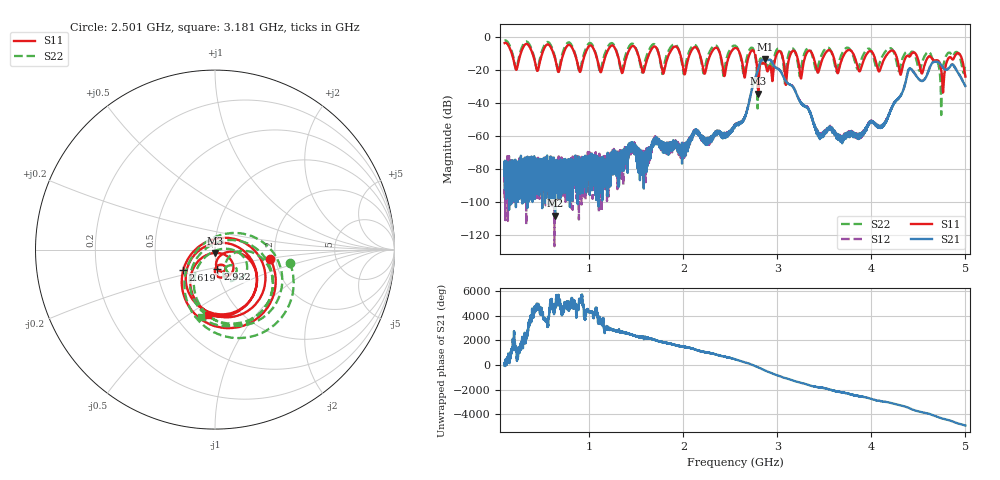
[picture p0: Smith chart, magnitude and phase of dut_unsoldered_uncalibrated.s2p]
!Keysight Technologies N9917A: A.13.25
!Date: Thursday, 15 October 2026 16:12:21
!Timezone: (UTC-08:00) Pacific Time (US & Canada)
!Model: N9917A
!Serial: MY56072049
!GPS Latitude:
!GPS Longitude:
!GPS TimeStamp: 0001-01-01 00:00:00Z
!GPS Seconds Since Last Read: 0
!CHECKSUM:0079315714
!Correction: S11(Rdy)S21(Rdy)S12(Rdy)S22(Rdy)
!S2P File: Measurements:S11,S21,S12,S22:
# Hz S DB R 50
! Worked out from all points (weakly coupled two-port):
!   10001 points, 100 MHz to 5 GHz, reference 50 ohm
!   highest |S21| = -13.83 dB at 2.866 GHz (marker M1); lowest = -108.2 dB at 637 MHz (marker M2)
!   lowest |S11| = -34.6 dB at 2.797 GHz (marker M3), VSWR 1.04, Z = 50.1 - j1.86 ohm
!   |S11| at or under -10 dB: 2.76 GHz to 3 GHz (239.7 MHz wide, 8.32 % of centre); 4.252 GHz to 4.434 GHz (181.4 MHz wide, 4.18 % of centre); 4.465 GHz to 4.916 GHz (451.4 MHz wide, 9.62 % of centre) (the widest 3 of 22)
!   |S22| runs from -47.4 to -2.4 dB; largest |S21 - S12| = 0.051
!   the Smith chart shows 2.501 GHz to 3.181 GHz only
!   S11 on the Smith chart (normalised r, x): 2.501 GHz: 1.87, -0.22; 2.619 GHz: 0.68, -0.16; 2.932 GHz: 1.00, -0.22; 3.181 GHz: 0.72, -0.60
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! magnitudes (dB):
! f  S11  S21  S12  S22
! 100 MHz  -4.0  -84.0  -77.1  -2.5
! 221 MHz  -20.0  -79.1  -80.2  -19.7
! 327.4 MHz  -4.5  -80.8  -79.7  -3.0
! 637 MHz  -13.4  -108.2  -76.5  -12.8
! 916.8 MHz  -18.9  -80.8  -85.9  -16.5
! 1.01 GHz  -5.4  -75.0  -75.8  -3.9
! 1.115 GHz  -21.0  -88.8  -86.7  -21.6
! 1.232 GHz  -5.6  -73.0  -75.1  -4.0
! 1.342 GHz  -21.0  -77.0  -74.3  -22.1
! 1.734 GHz  -9.5  -64.1  -64.5  -9.4
! 2.501 GHz  -10.1  -57.3  -56.9  -7.5
! 2.55 GHz  -6.9  -54.1  -53.5  -5.5
! 2.619 GHz  -13.5  -51.9  -51.9  -14.9
! 2.797 GHz  -34.6  -19.7  -19.5  -23.1
! 2.866 GHz  -16.0  -13.8  -13.6  -14.2
! 2.932 GHz  -19.3  -14.5  -14.3  -17.1
! 3.181 GHz  -8.7  -31.8  -31.6  -8.3
! 3.367 GHz  -10.0  -48.8  -48.7  -10.4
! 3.682 GHz  -14.4  -62.5  -62.1  -10.9
! 4.184 GHz  -9.7  -47.9  -47.5  -7.3
! 4.412 GHz  -11.8  -19.2  -18.9  -10.5
! 5 GHz  -24.2  -29.9  -29.7  -17.2
